One B-rep face of a CAD part: STEP entity #661.
In plain terms, the cylindrical face has radius 26.5 mm (diameter 53 mm), a partial arc.
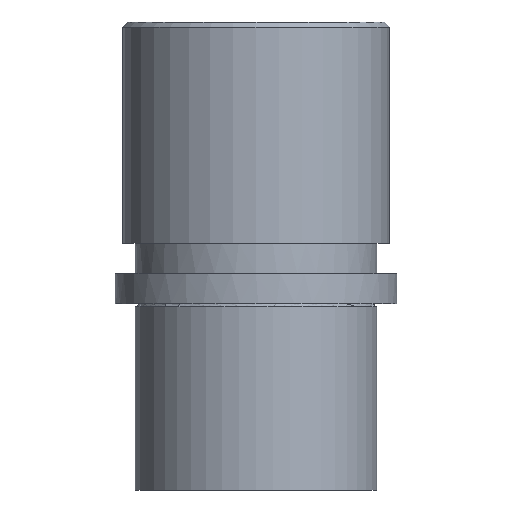
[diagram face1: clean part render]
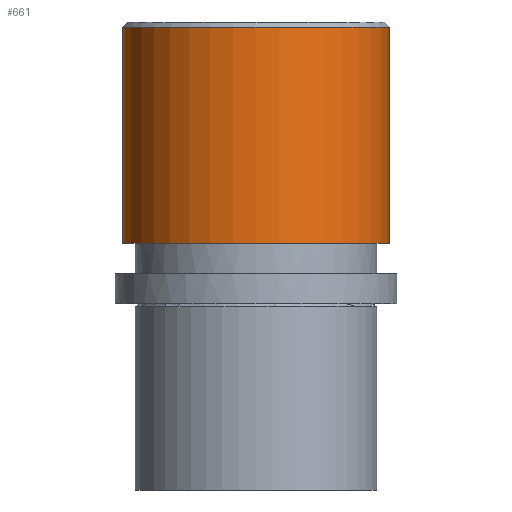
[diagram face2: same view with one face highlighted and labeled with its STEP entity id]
Its self-contained STEP definition (entity closure, numbers rounded to 3 decimals):
#505=CARTESIAN_POINT('Vertex',(-26.5,0.,55.)) ;
#512=CARTESIAN_POINT('Vertex',(26.5,0.,55.)) ;
#532=CARTESIAN_POINT('Axis2P3D Location',(0.,0.,55.)) ;
#619=CARTESIAN_POINT('Line Origine',(-26.5,0.,56.)) ;
#623=CARTESIAN_POINT('Vertex',(-26.5,0.,12.)) ;
#626=CARTESIAN_POINT('Line Origine',(26.5,0.,56.)) ;
#630=CARTESIAN_POINT('Vertex',(26.5,0.,12.)) ;
#645=CARTESIAN_POINT('Axis2P3D Location',(0.,0.,56.)) ;
#650=CARTESIAN_POINT('Axis2P3D Location',(0.,0.,12.)) ;
#533=DIRECTION('Axis2P3D Direction',(0.,0.,-1.)) ;
#620=DIRECTION('Vector Direction',(0.,0.,-1.)) ;
#627=DIRECTION('Vector Direction',(0.,0.,-1.)) ;
#646=DIRECTION('Axis2P3D Direction',(0.,0.,-1.)) ;
#647=DIRECTION('Axis2P3D XDirection',(1.,0.,0.)) ;
#651=DIRECTION('Axis2P3D Direction',(0.,0.,-1.)) ;
#534=AXIS2_PLACEMENT_3D('Circle Axis2P3D',#532,#533,$) ;
#648=AXIS2_PLACEMENT_3D('Cylinder Axis2P3D',#645,#646,#647) ;
#652=AXIS2_PLACEMENT_3D('Circle Axis2P3D',#650,#651,$) ;
#656=ORIENTED_EDGE('',*,*,#632,.T.) ;
#657=ORIENTED_EDGE('',*,*,#536,.F.) ;
#658=ORIENTED_EDGE('',*,*,#625,.T.) ;
#659=ORIENTED_EDGE('',*,*,#654,.T.) ;
#621=VECTOR('Line Direction',#620,1.) ;
#628=VECTOR('Line Direction',#627,1.) ;
#661=ADVANCED_FACE('734-30',(#660),#649,.T.) ;
#535=CIRCLE('generated circle',#534,26.5) ;
#653=CIRCLE('generated circle',#652,26.5) ;
#649=CYLINDRICAL_SURFACE('generated cylinder',#648,26.5) ;
#536=EDGE_CURVE('',#506,#513,#535,.F.) ;
#625=EDGE_CURVE('',#506,#624,#622,.T.) ;
#632=EDGE_CURVE('',#631,#513,#629,.F.) ;
#654=EDGE_CURVE('',#624,#631,#653,.F.) ;
#655=EDGE_LOOP('',(#656,#657,#658,#659)) ;
#660=FACE_OUTER_BOUND('',#655,.T.) ;
#622=LINE('Line',#619,#621) ;
#629=LINE('Line',#626,#628) ;
#506=VERTEX_POINT('',#505) ;
#513=VERTEX_POINT('',#512) ;
#624=VERTEX_POINT('',#623) ;
#631=VERTEX_POINT('',#630) ;
